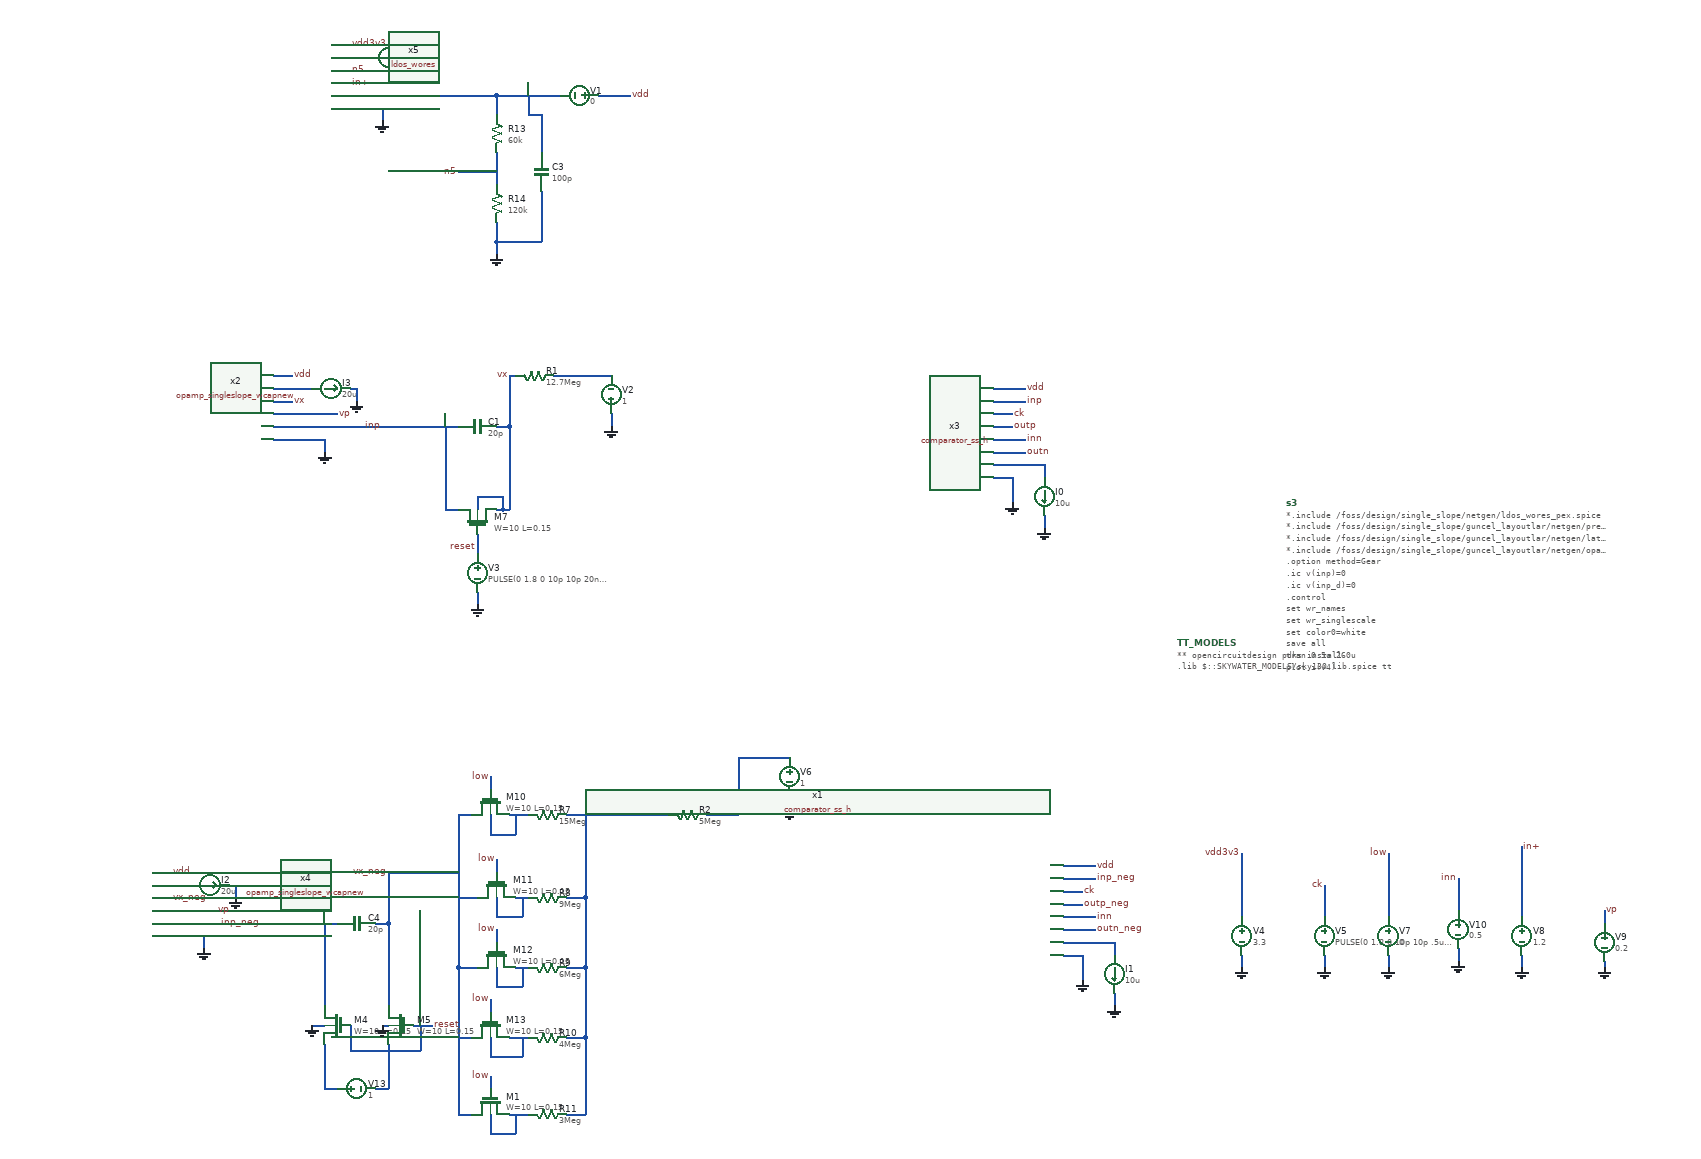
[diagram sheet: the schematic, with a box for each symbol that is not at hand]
v {xschem version=3.0.0 file_version=1.2 }
G {}
K {}
V {}
S {}
E {}
N 2440 -330 2440 -310 {
lab=GND}
N 2570 -330 2570 -310 {
lab=GND}
N 2570 -440 2570 -390 {
lab=ck}
N 2440 -490 2440 -390 {
lab=vdd3v3}
N 1450 -1180 1450 -1160 {
lab=GND}
N 1270 -1160 1290 -1160 {
lab=vx}
N 1290 -1240 1290 -1160 {
lab=vx}
N 1360 -1240 1450 -1240 {
lab=#net1}
N 1130 -1160 1210 -1160 {
lab=inp}
N 1190 -1030 1210 -1030 {
lab=inp}
N 1190 -1160 1190 -1030 {
lab=inp}
N 1270 -1030 1280 -1030 {
lab=vx}
N 1280 -1030 1290 -1030 {
lab=vx}
N 1290 -1160 1290 -1030 {
lab=vx}
N 1240 -1050 1240 -1030 {
lab=vx}
N 1240 -1050 1280 -1050 {
lab=vx}
N 1280 -1050 1280 -1030 {
lab=vx}
N 1240 -990 1240 -960 {
lab=reset}
N 1240 -900 1240 -880 {
lab=GND}
N 1030 -1160 1130 -1160 {
lab=inp}
N 1290 -1240 1300 -1240 {
lab=vx}
N 2780 -340 2780 -320 {
lab=GND}
N 2780 -450 2780 -400 {
lab=inn}
N 2080 -1080 2080 -1040 {
lab=GND}
N 2050 -1200 2100 -1200 {
lab=inp}
N 2050 -1140 2100 -1140 {
lab=inn}
N 2050 -1120 2100 -1120 {
lab=outn}
N 2050 -1180 2080 -1180 {
lab=ck}
N 2050 -1160 2080 -1160 {
lab=outp}
N 2050 -1220 2100 -1220 {
lab=vdd}
N 2050 -1080 2080 -1080 {
lab=GND}
N 2130 -1100 2130 -1080 {
lab=#net2}
N 2130 -1020 2130 -1000 {
lab=GND}
N 2050 -1100 2130 -1100 {
lab=#net2}
N 2190 -330 2190 -290 {
lab=GND}
N 2160 -450 2210 -450 {
lab=inp_neg}
N 2160 -390 2210 -390 {
lab=inn}
N 2160 -370 2210 -370 {
lab=outn_neg}
N 2160 -430 2190 -430 {
lab=ck}
N 2160 -410 2190 -410 {
lab=outp_neg}
N 2160 -470 2210 -470 {
lab=vdd}
N 2160 -330 2190 -330 {
lab=GND}
N 2240 -350 2240 -330 {
lab=#net3}
N 2240 -270 2240 -250 {
lab=GND}
N 2160 -350 2240 -350 {
lab=#net3}
N 1730 -580 1730 -560 {
lab=GND}
N 1080 -380 1100 -380 {
lab=vx_neg}
N 1100 -460 1100 -380 {
lab=vx_neg}
N 940 -380 1020 -380 {
lab=inp_neg}
N 1000 -380 1000 -250 {
lab=inp_neg}
N 1100 -380 1100 -250 {
lab=vx_neg}
N 840 -380 940 -380 {
lab=inp_neg}
N 1100 -460 1110 -460 {
lab=vx_neg}
N 1170 -460 1210 -460 {
lab=vx_neg}
N 1110 -460 1170 -460 {
lab=vx_neg}
N 2670 -330 2670 -310 {
lab=GND}
N 2670 -490 2670 -390 {
lab=low}
N 1650 -640 1650 -550 {
lab=#net4}
N 1610 -550 1650 -550 {
lab=#net4}
N 1430 -550 1470 -550 {
lab=#net5}
N 1470 -550 1530 -550 {
lab=#net5}
N 1650 -640 1730 -640 {
lab=#net4}
N 920 -1240 950 -1240 {
lab=vdd}
N 920 -1200 950 -1200 {
lab=vx}
N 920 -1180 1000 -1180 {
lab=vp}
N 920 -1160 940 -1160 {
lab=inp}
N 920 -1140 1000 -1140 {
lab=GND}
N 1000 -1140 1000 -1120 {
lab=GND}
N 940 -1160 1030 -1160 {
lab=inp}
N 1000 -1180 1020 -1180 {
lab=vp}
N 1050 -1220 1050 -1200 {
lab=GND}
N 920 -1220 980 -1220 {
lab=#net6}
N 1040 -1220 1050 -1220 {
lab=GND}
N 730 -460 760 -460 {
lab=vdd}
N 730 -420 760 -420 {
lab=vx_neg}
N 730 -400 810 -400 {
lab=vp}
N 730 -380 750 -380 {
lab=inp_neg}
N 730 -360 810 -360 {
lab=GND}
N 810 -360 810 -340 {
lab=GND}
N 750 -380 840 -380 {
lab=inp_neg}
N 810 -400 830 -400 {
lab=vp}
N 860 -440 860 -420 {
lab=GND}
N 730 -440 790 -440 {
lab=#net7}
N 850 -440 860 -440 {
lab=GND}
N 1530 -550 1540 -550 {
lab=#net5}
N 1600 -550 1610 -550 {
lab=#net4}
N 1270 -1450 1270 -1430 {
lab=GND}
N 1270 -1590 1270 -1540 {
lab=n5}
N 1270 -1680 1270 -1650 {
lab=#net8}
N 1270 -1680 1370 -1680 {
lab=#net8}
N 1270 -1480 1270 -1450 {
lab=GND}
N 1210 -1560 1270 -1560 {
lab=n5}
N 1430 -1680 1480 -1680 {
lab=vdd}
N 1340 -1650 1340 -1590 {
lab=#net8}
N 1320 -1650 1340 -1650 {
lab=#net8}
N 1320 -1680 1320 -1650 {
lab=#net8}
N 1340 -1530 1340 -1450 {
lab=GND}
N 1270 -1450 1340 -1450 {
lab=GND}
N 1010 -1760 1040 -1760 {
lab=vdd3v3}
N 1010 -1720 1040 -1720 {
lab=n5}
N 1010 -1680 1030 -1680 {
lab=#net8}
N 1010 -1660 1090 -1660 {
lab=GND}
N 1090 -1660 1090 -1640 {
lab=GND}
N 1140 -1740 1140 -1720 {
lab=GND}
N 1010 -1740 1070 -1740 {
lab=#net9}
N 1130 -1740 1140 -1740 {
lab=GND}
N 1010 -1700 1040 -1700 {
lab=in+}
N 1030 -1680 1040 -1680 {
lab=#net8}
N 1040 -1680 1160 -1680 {
lab=#net8}
N 1160 -1680 1210 -1680 {
lab=#net8}
N 1210 -1680 1270 -1680 {
lab=#net8}
N 2880 -410 2880 -390 {
lab=in+}
N 2880 -330 2880 -310 {
lab=GND}
N 2880 -420 2880 -410 {
lab=in+}
N 2880 -430 2880 -420 {
lab=in+}
N 2880 -500 2880 -490 {
lab=in+}
N 2880 -490 2880 -430 {
lab=in+}
N 3010 -320 3010 -310 {
lab=GND}
N 3010 -400 3010 -380 {
lab=vp}
N 1290 -550 1320 -550 {
lab=#net10}
N 1210 -550 1230 -550 {
lab=vx_neg}
N 1210 -550 1210 -370 {
lab=vx_neg}
N 1260 -550 1260 -520 {
lab=#net10}
N 1270 -420 1270 -390 {
lab=#net11}
N 1270 -310 1270 -280 {
lab=#net12}
N 1260 -200 1260 -170 {
lab=#net13}
N 1260 -80 1260 -50 {
lab=#net14}
N 1210 -420 1240 -420 {
lab=vx_neg}
N 1300 -420 1320 -420 {
lab=#net11}
N 1210 -370 1210 -310 {
lab=vx_neg}
N 1210 -310 1240 -310 {
lab=vx_neg}
N 1300 -310 1320 -310 {
lab=#net12}
N 1410 -550 1410 -420 {
lab=#net5}
N 1380 -420 1410 -420 {
lab=#net5}
N 1410 -420 1410 -310 {
lab=#net5}
N 1380 -310 1410 -310 {
lab=#net5}
N 1410 -310 1410 -200 {
lab=#net5}
N 1380 -200 1410 -200 {
lab=#net5}
N 1410 -200 1410 -80 {
lab=#net5}
N 1380 -80 1410 -80 {
lab=#net5}
N 1210 -310 1210 -80 {
lab=vx_neg}
N 1210 -80 1230 -80 {
lab=vx_neg}
N 1210 -200 1230 -200 {
lab=vx_neg}
N 1290 -200 1320 -200 {
lab=#net13}
N 1290 -80 1320 -80 {
lab=#net14}
N 1260 -610 1260 -590 {
lab=low}
N 1270 -480 1270 -460 {
lab=low}
N 1270 -370 1270 -350 {
lab=low}
N 1260 -260 1260 -240 {
lab=low}
N 1260 -140 1260 -120 {
lab=low}
N 1380 -550 1430 -550 {
lab=#net5}
N 1260 -520 1300 -520 {
lab=#net10}
N 1300 -550 1300 -520 {
lab=#net10}
N 1270 -390 1310 -390 {
lab=#net11}
N 1310 -420 1310 -390 {
lab=#net11}
N 1270 -280 1310 -280 {
lab=#net12}
N 1310 -310 1310 -280 {
lab=#net12}
N 1260 -170 1310 -170 {
lab=#net13}
N 1310 -200 1310 -170 {
lab=#net13}
N 1260 -50 1300 -50 {
lab=#net14}
N 1300 -80 1300 -50 {
lab=#net14}
N 1000 -120 1020 -120 {
lab=#net15}
N 1080 -120 1100 -120 {
lab=#net16}
N 1000 -190 1000 -120 {
lab=#net15}
N 1100 -190 1100 -120 {
lab=#net16}
N 980 -220 1000 -220 {
lab=GND}
N 1090 -220 1100 -220 {
lab=GND}
N 1140 -220 1170 -220 {
lab=reset}
N 1040 -220 1040 -180 {
lab=reset}
N 1040 -180 1150 -180 {
lab=reset}
N 1150 -220 1150 -180 {
lab=reset}
C {devices/vsource.sym} 2440 -360 0 0 {name=V4 value=3.3
}
C {devices/gnd.sym} 2440 -310 0 0 {name=l33 lab=GND}
C {devices/lab_pin.sym} 2440 -490 0 0 {name=l34 sig_type=std_logic lab=vdd3v3}
C {devices/vsource.sym} 2570 -360 0 0 {name=V5 value="PULSE(0 1.8 0 10p 10p .5u 1u)"
}
C {devices/gnd.sym} 2570 -310 0 0 {name=l35 lab=GND}
C {devices/lab_pin.sym} 2570 -440 0 0 {name=l36 sig_type=std_logic lab=ck}
C {devices/capa.sym} 1240 -1160 1 0 {name=C1
m=1
value=20p
footprint=1206
device="ceramic capacitor"}
C {devices/vsource.sym} 1450 -1210 2 0 {name=V2 value=1}
C {devices/gnd.sym} 1450 -1160 0 0 {name=l5 lab=GND}
C {devices/res.sym} 1330 -1240 1 0 {name=R1
value=12.7Meg
footprint=1206
device=resistor
m=1}
C {devices/lab_pin.sym} 1290 -1240 1 0 {name=l6 sig_type=std_logic lab=vx}
C {pdk/sky130A/libs.tech/xschem/sky130_fd_pr/nfet_01v8.sym} 1240 -1010 3 0 {name=M7
L=0.15
W=10
nf=1 
mult=1
ad="'int((nf+1)/2) * W/nf * 0.29'" 
pd="'2*int((nf+1)/2) * (W/nf + 0.29)'"
as="'int((nf+2)/2) * W/nf * 0.29'" 
ps="'2*int((nf+2)/2) * (W/nf + 0.29)'"
nrd="'0.29 / W'" nrs="'0.29 / W'"
sa=0 sb=0 sd=0
model=nfet_01v8
spiceprefix=X
}
C {devices/vsource.sym} 1240 -930 0 0 {name=V3 value="PULSE(0 1.8 0 10p 10p 20n 256.02u)"}
C {devices/gnd.sym} 1240 -880 0 0 {name=l7 lab=GND}
C {devices/lab_pin.sym} 1240 -970 0 0 {name=l49 sig_type=std_logic lab=reset}
C {devices/code.sym} 2340 -820 0 0 {name=TT_MODELS
only_toplevel=true
format="tcleval( @value )"
value="
** opencircuitdesign pdks install
.lib $::SKYWATER_MODELS/sky130.lib.spice tt

"
spice_ignore=false}
C {devices/code_shown.sym} 2510 -1040 0 0 {name=s3 only_toplevel=false value="

*.include /foss/design/single_slope/netgen/ldos_wores_pex.spice
*.include /foss/design/single_slope/guncel_layoutlar/netgen/preamp_singleslope_new_pex.spice
*.include /foss/design/single_slope/guncel_layoutlar/netgen/latch_singleslope_new_pex.spice
*.include /foss/design/single_slope/guncel_layoutlar/netgen/opamp_singleslope_addcap_pex.spice
.option method=Gear 
.ic v(inp)=0 
.ic v(inp_d)=0
.control
set wr_names 
set wr_singlescale
set color0=white
save all
tran 0.5u 260u

plot i(v4)
plot inp inp_neg
plot inp inn outp outn
plot inp_neg inn outp_neg outn_neg

*show all
.endc
"}
C {devices/lab_pin.sym} 1090 -1160 1 0 {name=l22 sig_type=std_logic lab=inp}
C {devices/vsource.sym} 2780 -370 0 0 {name=V10 value=0.5}
C {devices/gnd.sym} 2780 -320 0 0 {name=l41 lab=GND}
C {devices/lab_pin.sym} 2780 -450 0 0 {name=l47 sig_type=std_logic lab=inn}
C {devices/gnd.sym} 2080 -1040 0 0 {name=l8 lab=GND}
C {devices/lab_pin.sym} 2100 -1220 0 1 {name=l14 sig_type=std_logic lab=vdd}
C {devices/lab_pin.sym} 2080 -1180 0 1 {name=l15 sig_type=std_logic lab=ck}
C {devices/lab_pin.sym} 2100 -1200 0 1 {name=l16 sig_type=std_logic lab=inp}
C {devices/lab_pin.sym} 2100 -1140 0 1 {name=l17 sig_type=std_logic lab=inn}
C {devices/lab_pin.sym} 2080 -1160 0 1 {name=l18 sig_type=std_logic lab=outp}
C {devices/lab_pin.sym} 2100 -1120 0 1 {name=l19 sig_type=std_logic lab=outn}
C {devices/isource.sym} 2130 -1050 0 0 {name=I0 value=10u}
C {devices/gnd.sym} 2130 -1000 0 0 {name=l59 lab=GND}
C {devices/gnd.sym} 2190 -290 0 0 {name=l9 lab=GND}
C {devices/lab_pin.sym} 2210 -470 0 1 {name=l25 sig_type=std_logic lab=vdd}
C {devices/lab_pin.sym} 2190 -430 0 1 {name=l26 sig_type=std_logic lab=ck}
C {devices/lab_pin.sym} 2210 -450 0 1 {name=l27 sig_type=std_logic lab=inp_neg}
C {devices/lab_pin.sym} 2210 -390 0 1 {name=l31 sig_type=std_logic lab=inn}
C {devices/lab_pin.sym} 2190 -410 0 1 {name=l32 sig_type=std_logic lab=outp_neg}
C {devices/lab_pin.sym} 2210 -370 0 1 {name=l37 sig_type=std_logic lab=outn_neg}
C {devices/isource.sym} 2240 -300 0 0 {name=I1 value=10u}
C {devices/gnd.sym} 2240 -250 0 0 {name=l38 lab=GND}
C {devices/capa.sym} 1050 -380 1 0 {name=C4
m=1
value=20p
footprint=1206
device="ceramic capacitor"}
C {devices/vsource.sym} 1730 -610 0 0 {name=V6 value=1}
C {devices/gnd.sym} 1730 -560 0 0 {name=l39 lab=GND}
C {devices/lab_pin.sym} 1100 -460 1 0 {name=l40 sig_type=std_logic lab=vx_neg}
C {devices/lab_pin.sym} 900 -380 1 0 {name=l45 sig_type=std_logic lab=inp_neg}
C {devices/vsource.sym} 2670 -360 0 0 {name=V7 value=0
}
C {devices/gnd.sym} 2670 -310 0 0 {name=l3 lab=GND}
C {devices/lab_pin.sym} 2670 -490 0 0 {name=l4 sig_type=std_logic lab=low}
C {design/single_slope/comparator_ss_h.sym} 1900 -1150 0 0 {name=x3}
C {design/single_slope/comparator_ss_h.sym} 2010 -400 0 0 {name=x1}
C {devices/lab_pin.sym} 950 -1240 2 0 {name=l2 sig_type=std_logic lab=vdd}
C {devices/lab_pin.sym} 950 -1200 2 0 {name=l20 sig_type=std_logic lab=vx}
C {devices/gnd.sym} 1000 -1120 0 0 {name=l21 lab=GND}
C {devices/isource.sym} 1010 -1220 3 0 {name=I3 value=20u}
C {devices/gnd.sym} 1050 -1200 0 0 {name=l11 lab=GND}
C {design/single_slope/opamp_singleslope_wcapnew.sym} 770 -1190 0 0 {name=x2}
C {devices/lab_pin.sym} 760 -460 2 0 {name=l12 sig_type=std_logic lab=vdd}
C {devices/lab_pin.sym} 760 -420 2 0 {name=l13 sig_type=std_logic lab=vx_neg}
C {devices/gnd.sym} 810 -340 0 0 {name=l23 lab=GND}
C {devices/isource.sym} 820 -440 3 0 {name=I2 value=20u}
C {devices/gnd.sym} 860 -420 0 0 {name=l28 lab=GND}
C {design/single_slope/opamp_singleslope_wcapnew.sym} 580 -410 0 0 {name=x4}
C {devices/res.sym} 1570 -550 1 0 {name=R2
value=5Meg
footprint=1206
device=resistor
m=1}
C {devices/gnd.sym} 1270 -1430 0 0 {name=l156 lab=GND}
C {devices/res.sym} 1270 -1620 0 0 {name=R13
value=60k
footprint=1206
device=resistor
m=1}
C {devices/res.sym} 1270 -1510 0 0 {name=R14
value=120k
footprint=1206
device=resistor
m=1}
C {devices/lab_pin.sym} 1210 -1560 0 0 {name=l100 sig_type=std_logic lab=n5}
C {devices/lab_pin.sym} 1480 -1680 0 1 {name=l101 sig_type=std_logic lab=vdd}
C {devices/vsource.sym} 1400 -1680 1 0 {name=V1 value=0}
C {devices/capa.sym} 1340 -1560 0 0 {name=C3
m=1
value=100p
footprint=1206
device="ceramic capacitor"}
C {devices/lab_pin.sym} 1040 -1760 2 0 {name=l10 sig_type=std_logic lab=vdd3v3}
C {devices/lab_pin.sym} 1040 -1720 2 0 {name=l30 sig_type=std_logic lab=n5}
C {devices/gnd.sym} 1090 -1640 0 0 {name=l43 lab=GND}
C {devices/lab_pin.sym} 1040 -1700 2 0 {name=l44 sig_type=std_logic lab=in+}
C {devices/isource.sym} 1100 -1740 3 0 {name=I4 value=15u}
C {devices/gnd.sym} 1140 -1720 0 0 {name=l46 lab=GND}
C {design/ldo/ldos_wores.sym} 860 -1710 0 0 {name=x5}
C {devices/vsource.sym} 2880 -360 0 0 {name=V8 value=1.2}
C {devices/gnd.sym} 2880 -310 0 0 {name=l53 lab=GND}
C {devices/lab_pin.sym} 2880 -500 2 0 {name=l54 sig_type=std_logic lab=in+}
C {devices/vsource.sym} 3010 -350 0 0 {name=V9 value=0.2}
C {devices/gnd.sym} 3010 -310 0 1 {name=l55 lab=GND}
C {devices/lab_pin.sym} 3010 -400 2 0 {name=l56 sig_type=std_logic lab=vp}
C {devices/lab_pin.sym} 830 -400 2 0 {name=l1 sig_type=std_logic lab=vp}
C {devices/lab_pin.sym} 1020 -1180 2 0 {name=l24 sig_type=std_logic lab=vp}
C {devices/res.sym} 1350 -550 1 0 {name=R7
value=15Meg
footprint=1206
device=resistor
m=1}
C {devices/res.sym} 1350 -420 1 0 {name=R8
value=9Meg
footprint=1206
device=resistor
m=1}
C {devices/res.sym} 1350 -310 1 0 {name=R9
value=6Meg
footprint=1206
device=resistor
m=1}
C {devices/res.sym} 1350 -200 1 0 {name=R10
value=4Meg
footprint=1206
device=resistor
m=1}
C {devices/res.sym} 1350 -80 1 0 {name=R11
value=3Meg
footprint=1206
device=resistor
m=1}
C {pdk/sky130A/libs.tech/xschem/sky130_fd_pr/nfet_01v8.sym} 1260 -570 3 1 {name=M10
L=0.15
W=10
nf=1 
mult=1
ad="'int((nf+1)/2) * W/nf * 0.29'" 
pd="'2*int((nf+1)/2) * (W/nf + 0.29)'"
as="'int((nf+2)/2) * W/nf * 0.29'" 
ps="'2*int((nf+2)/2) * (W/nf + 0.29)'"
nrd="'0.29 / W'" nrs="'0.29 / W'"
sa=0 sb=0 sd=0
model=nfet_01v8
spiceprefix=X
}
C {pdk/sky130A/libs.tech/xschem/sky130_fd_pr/nfet_01v8.sym} 1270 -440 3 1 {name=M11
L=0.15
W=10
nf=1 
mult=1
ad="'int((nf+1)/2) * W/nf * 0.29'" 
pd="'2*int((nf+1)/2) * (W/nf + 0.29)'"
as="'int((nf+2)/2) * W/nf * 0.29'" 
ps="'2*int((nf+2)/2) * (W/nf + 0.29)'"
nrd="'0.29 / W'" nrs="'0.29 / W'"
sa=0 sb=0 sd=0
model=nfet_01v8
spiceprefix=X
}
C {pdk/sky130A/libs.tech/xschem/sky130_fd_pr/nfet_01v8.sym} 1270 -330 3 1 {name=M12
L=0.15
W=10
nf=1 
mult=1
ad="'int((nf+1)/2) * W/nf * 0.29'" 
pd="'2*int((nf+1)/2) * (W/nf + 0.29)'"
as="'int((nf+2)/2) * W/nf * 0.29'" 
ps="'2*int((nf+2)/2) * (W/nf + 0.29)'"
nrd="'0.29 / W'" nrs="'0.29 / W'"
sa=0 sb=0 sd=0
model=nfet_01v8
spiceprefix=X
}
C {pdk/sky130A/libs.tech/xschem/sky130_fd_pr/nfet_01v8.sym} 1260 -220 3 1 {name=M13
L=0.15
W=10
nf=1 
mult=1
ad="'int((nf+1)/2) * W/nf * 0.29'" 
pd="'2*int((nf+1)/2) * (W/nf + 0.29)'"
as="'int((nf+2)/2) * W/nf * 0.29'" 
ps="'2*int((nf+2)/2) * (W/nf + 0.29)'"
nrd="'0.29 / W'" nrs="'0.29 / W'"
sa=0 sb=0 sd=0
model=nfet_01v8
spiceprefix=X
}
C {pdk/sky130A/libs.tech/xschem/sky130_fd_pr/nfet_01v8.sym} 1260 -100 3 1 {name=M1
L=0.15
W=10
nf=1 
mult=1
ad="'int((nf+1)/2) * W/nf * 0.29'" 
pd="'2*int((nf+1)/2) * (W/nf + 0.29)'"
as="'int((nf+2)/2) * W/nf * 0.29'" 
ps="'2*int((nf+2)/2) * (W/nf + 0.29)'"
nrd="'0.29 / W'" nrs="'0.29 / W'"
sa=0 sb=0 sd=0
model=nfet_01v8
spiceprefix=X
}
C {devices/lab_pin.sym} 1260 -610 0 0 {name=l63 sig_type=std_logic lab=low}
C {devices/lab_pin.sym} 1270 -480 0 0 {name=l64 sig_type=std_logic lab=low}
C {devices/lab_pin.sym} 1270 -370 0 0 {name=l65 sig_type=std_logic lab=low}
C {devices/lab_pin.sym} 1260 -260 0 0 {name=l66 sig_type=std_logic lab=low}
C {devices/lab_pin.sym} 1260 -140 0 0 {name=l67 sig_type=std_logic lab=low}
C {devices/vsource.sym} 1050 -120 3 0 {name=V13 value=1}
C {devices/lab_pin.sym} 1170 -220 0 1 {name=l42 sig_type=std_logic lab=reset}
C {pdk/sky130A/libs.tech/xschem/sky130_fd_pr/nfet_01v8.sym} 1020 -220 2 0 {name=M4
L=0.15
W=10
nf=1 
mult=1
ad="'int((nf+1)/2) * W/nf * 0.29'" 
pd="'2*int((nf+1)/2) * (W/nf + 0.29)'"
as="'int((nf+2)/2) * W/nf * 0.29'" 
ps="'2*int((nf+2)/2) * (W/nf + 0.29)'"
nrd="'0.29 / W'" nrs="'0.29 / W'"
sa=0 sb=0 sd=0
model=nfet_01v8
spiceprefix=X
}
C {pdk/sky130A/libs.tech/xschem/sky130_fd_pr/nfet_01v8.sym} 1120 -220 2 0 {name=M5
L=0.15
W=10
nf=1 
mult=1
ad="'int((nf+1)/2) * W/nf * 0.29'" 
pd="'2*int((nf+1)/2) * (W/nf + 0.29)'"
as="'int((nf+2)/2) * W/nf * 0.29'" 
ps="'2*int((nf+2)/2) * (W/nf + 0.29)'"
nrd="'0.29 / W'" nrs="'0.29 / W'"
sa=0 sb=0 sd=0
model=nfet_01v8
spiceprefix=X
}
C {devices/gnd.sym} 980 -220 0 0 {name=l68 lab=GND}
C {devices/gnd.sym} 1090 -220 0 0 {name=l69 lab=GND}
